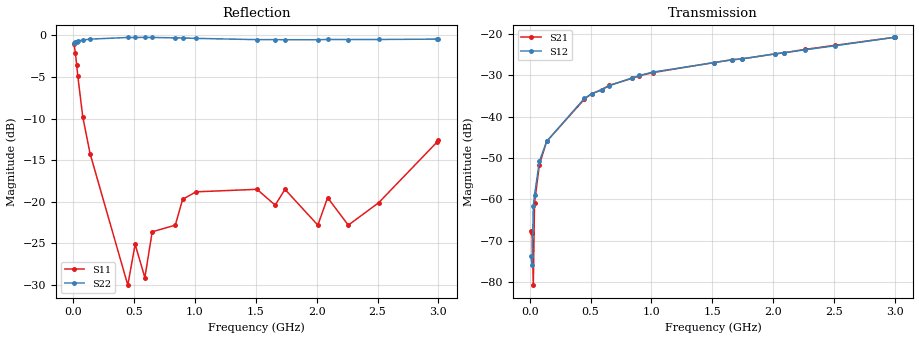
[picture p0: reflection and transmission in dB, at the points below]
! "!Agilent Technologies,E5071B,MY42403564,A.08.11"
!Date: Wed Apr 07 12:18:44 2010
!Data & Calibration Information:
!Freq
# Hz S dB R 50
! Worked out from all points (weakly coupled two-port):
!   300 points, 10 MHz to 3 GHz, reference 50 ohm
!   highest |S21| = -20.90 dB at 2.99 GHz (marker M1); lowest = -80.7 dB at 30 MHz (marker M2)
!   lowest |S11| = -30.0 dB at 450 MHz (marker M3), VSWR 1.07, Z = 53 - j1.35 ohm
!   |S11| at or under -10 dB: 82.16 MHz to end of sweep
!   |S22| runs from -0.9 to -0.3 dB; largest |S21 - S12| = 0.0019
!   S11 on the Smith chart (normalised r, x): 10 MHz: 0.06, +0.13; 40 MHz: 0.35, +0.48; 900 MHz: 0.84, -0.11; 3 GHz: 0.78, +0.37
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1e7  -1.11 165.0  -67.60 126.0  -73.70 153.0  -0.91 152.0
2e7  -2.18 147.0  -68.20 177.0  -75.80 140.0  -0.83 113.0
3e7  -3.54 134.0  -80.70 111.0  -61.60 -177.0  -0.76 87.1
4e7  -4.94 124.0  -60.90 154.0  -59.00 145.0  -0.70 69.0
8e7  -9.78 101.0  -51.60 119.0  -50.80 121.0  -0.58 32.2
1.4e8  -14.20 83.1  -46.00 103.0  -46.00 99.2  -0.47 8.9
4.5e8  -30.00 -23.7  -35.80 53.2  -35.60 53.5  -0.27 -42.6
5.1e8  -25.10 -54.9  -34.50 46.1  -34.50 46.2  -0.27 -50.7
5.9e8  -29.10 -91.1  -33.50 38.1  -33.60 37.5  -0.26 -61.0
6.5e8  -23.60 -98.1  -32.50 30.9  -32.60 31.0  -0.27 -68.0
8.4e8  -22.80 -135.0  -30.80 11.7  -30.70 11.3  -0.32 -91.3
9e8  -19.70 -142.0  -30.20 4.3  -30.10 4.5  -0.33 -98.2
1.01e9  -18.80 -154.0  -29.40 -6.0  -29.30 -6.5  -0.38 -111.0
1.51e9  -18.50 148.0  -27.00 -51.0  -27.00 -51.0  -0.53 -167.0
1.66e9  -20.40 142.0  -26.30 -62.7  -26.30 -63.0  -0.53 177.0
1.74e9  -18.50 133.0  -26.10 -70.9  -26.10 -71.3  -0.54 169.0
2.01e9  -22.80 132.0  -24.90 -91.3  -24.90 -91.4  -0.54 142.0
2.09e9  -19.50 130.0  -24.60 -98.9  -24.60 -98.6  -0.51 134.0
2.26e9  -22.80 130.0  -23.80 -111.0  -23.90 -112.0  -0.52 117.0
2.51e9  -20.10 135.0  -22.80 -132.0  -22.90 -132.0  -0.51 92.5
2.99e9  -12.80 110.0  -20.90 -175.0  -20.90 -175.0  -0.47 46.2
3e9  -12.60 109.0  -20.90 -176.0  -20.90 -176.0  -0.47 45.2
